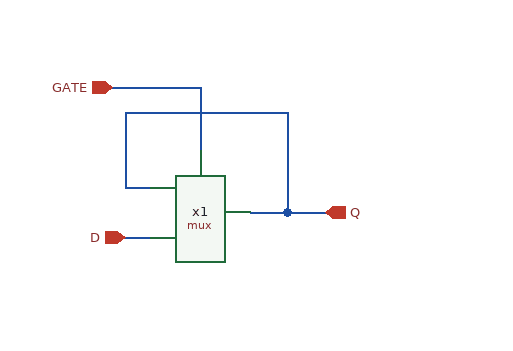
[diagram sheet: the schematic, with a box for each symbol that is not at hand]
v {xschem version=3.4.8RC file_version=1.3}
G {}
K {}
V {}
S {}
F {}
E {}
N 80 -40 110 -40 {lab=X}
N 110 -120 110 -40 {lab=X}
N -20 -120 110 -120 {lab=X}
N -20 -120 -20 -60 {lab=X}
N -20 -60 -0 -60 {lab=X}
N -30 -140 40 -140 {lab=GATE}
N 40 -140 40 -90 {lab=GATE}
N -20 -20 -0 -20 {lab=D}
N 110 -40 140 -40 {lab=X}
C {/home/luemmel/Dokumente/Studienarbeit/new_lib/schematics/mux.sym} 0 0 0 0 {name=x1

WN=840n
WP=550n}
C {ipin.sym} -20 -20 0 0 {name=p1 lab=D}
C {opin.sym} 140 -40 0 0 {name=p2 lab=Q}
C {ipin.sym} -30 -140 0 0 {name=p3 lab=GATE}
